# Generated by FakeRAM 2.0
VERSION 5.7 ;
BUSBITCHARS "[]" ;
PROPERTYDEFINITIONS
  MACRO width INTEGER ;
  MACRO depth INTEGER ;
  MACRO banks INTEGER ;
END PROPERTYDEFINITIONS
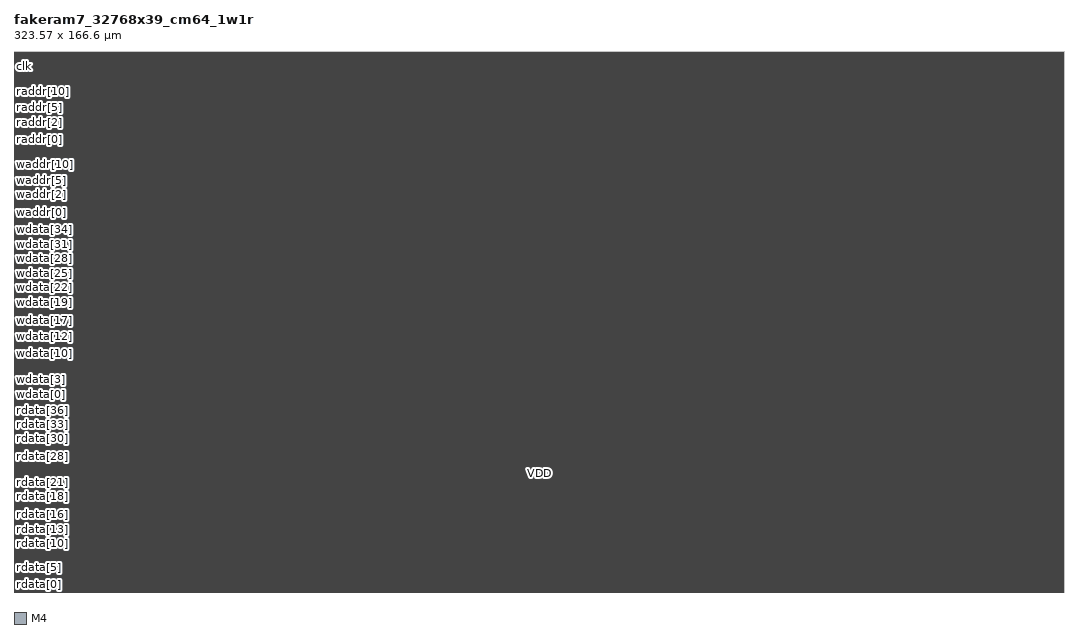
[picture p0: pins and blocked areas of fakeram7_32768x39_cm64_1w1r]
MACRO fakeram7_32768x39_cm64_1w1r
  PROPERTY width 39 ;
  PROPERTY depth 32768 ;
  PROPERTY banks 1 ;
  FOREIGN fakeram7_32768x39_cm64_1w1r 0 0 ;
  SYMMETRY X Y R90 ;
  SIZE 323.5700 BY 166.6000 ;
  CLASS BLOCK ;
  PIN wdata[0]
    DIRECTION INPUT ;
    USE SIGNAL ;
    PORT
      LAYER M4 ;
      RECT 0.00000 58.51200 0.02400 58.53600 ;
    END
  END wdata[0]
  PIN wdata[1]
    DIRECTION INPUT ;
    USE SIGNAL ;
    PORT
      LAYER M4 ;
      RECT 0.00000 60.00000 0.02400 60.02400 ;
    END
  END wdata[1]
  PIN wdata[2]
    DIRECTION INPUT ;
    USE SIGNAL ;
    PORT
      LAYER M4 ;
      RECT 0.00000 61.48800 0.02400 61.51200 ;
    END
  END wdata[2]
  PIN wdata[3]
    DIRECTION INPUT ;
    USE SIGNAL ;
    PORT
      LAYER M4 ;
      RECT 0.00000 62.97600 0.02400 63.00000 ;
    END
  END wdata[3]
  PIN wdata[4]
    DIRECTION INPUT ;
    USE SIGNAL ;
    PORT
      LAYER M4 ;
      RECT 0.00000 64.46400 0.02400 64.48800 ;
    END
  END wdata[4]
  PIN wdata[5]
    DIRECTION INPUT ;
    USE SIGNAL ;
    PORT
      LAYER M4 ;
      RECT 0.00000 65.95200 0.02400 65.97600 ;
    END
  END wdata[5]
  PIN wdata[6]
    DIRECTION INPUT ;
    USE SIGNAL ;
    PORT
      LAYER M4 ;
      RECT 0.00000 67.44000 0.02400 67.46400 ;
    END
  END wdata[6]
  PIN wdata[7]
    DIRECTION INPUT ;
    USE SIGNAL ;
    PORT
      LAYER M4 ;
      RECT 0.00000 68.92800 0.02400 68.95200 ;
    END
  END wdata[7]
  PIN wdata[8]
    DIRECTION INPUT ;
    USE SIGNAL ;
    PORT
      LAYER M4 ;
      RECT 0.00000 70.41600 0.02400 70.44000 ;
    END
  END wdata[8]
  PIN wdata[9]
    DIRECTION INPUT ;
    USE SIGNAL ;
    PORT
      LAYER M4 ;
      RECT 0.00000 71.90400 0.02400 71.92800 ;
    END
  END wdata[9]
  PIN wdata[10]
    DIRECTION INPUT ;
    USE SIGNAL ;
    PORT
      LAYER M4 ;
      RECT 0.00000 73.39200 0.02400 73.41600 ;
    END
  END wdata[10]
  PIN wdata[11]
    DIRECTION INPUT ;
    USE SIGNAL ;
    PORT
      LAYER M4 ;
      RECT 0.00000 74.88000 0.02400 74.90400 ;
    END
  END wdata[11]
  PIN wdata[12]
    DIRECTION INPUT ;
    USE SIGNAL ;
    PORT
      LAYER M4 ;
      RECT 0.00000 76.36800 0.02400 76.39200 ;
    END
  END wdata[12]
  PIN wdata[13]
    DIRECTION INPUT ;
    USE SIGNAL ;
    PORT
      LAYER M4 ;
      RECT 0.00000 77.85600 0.02400 77.88000 ;
    END
  END wdata[13]
  PIN wdata[14]
    DIRECTION INPUT ;
    USE SIGNAL ;
    PORT
      LAYER M4 ;
      RECT 0.00000 79.34400 0.02400 79.36800 ;
    END
  END wdata[14]
  PIN wdata[15]
    DIRECTION INPUT ;
    USE SIGNAL ;
    PORT
      LAYER M4 ;
      RECT 0.00000 80.83200 0.02400 80.85600 ;
    END
  END wdata[15]
  PIN wdata[16]
    DIRECTION INPUT ;
    USE SIGNAL ;
    PORT
      LAYER M4 ;
      RECT 0.00000 82.32000 0.02400 82.34400 ;
    END
  END wdata[16]
  PIN wdata[17]
    DIRECTION INPUT ;
    USE SIGNAL ;
    PORT
      LAYER M4 ;
      RECT 0.00000 83.80800 0.02400 83.83200 ;
    END
  END wdata[17]
  PIN wdata[18]
    DIRECTION INPUT ;
    USE SIGNAL ;
    PORT
      LAYER M4 ;
      RECT 0.00000 85.29600 0.02400 85.32000 ;
    END
  END wdata[18]
  PIN wdata[19]
    DIRECTION INPUT ;
    USE SIGNAL ;
    PORT
      LAYER M4 ;
      RECT 0.00000 86.78400 0.02400 86.80800 ;
    END
  END wdata[19]
  PIN wdata[20]
    DIRECTION INPUT ;
    USE SIGNAL ;
    PORT
      LAYER M4 ;
      RECT 0.00000 88.27200 0.02400 88.29600 ;
    END
  END wdata[20]
  PIN wdata[21]
    DIRECTION INPUT ;
    USE SIGNAL ;
    PORT
      LAYER M4 ;
      RECT 0.00000 89.76000 0.02400 89.78400 ;
    END
  END wdata[21]
  PIN wdata[22]
    DIRECTION INPUT ;
    USE SIGNAL ;
    PORT
      LAYER M4 ;
      RECT 0.00000 91.24800 0.02400 91.27200 ;
    END
  END wdata[22]
  PIN wdata[23]
    DIRECTION INPUT ;
    USE SIGNAL ;
    PORT
      LAYER M4 ;
      RECT 0.00000 92.73600 0.02400 92.76000 ;
    END
  END wdata[23]
  PIN wdata[24]
    DIRECTION INPUT ;
    USE SIGNAL ;
    PORT
      LAYER M4 ;
      RECT 0.00000 94.22400 0.02400 94.24800 ;
    END
  END wdata[24]
  PIN wdata[25]
    DIRECTION INPUT ;
    USE SIGNAL ;
    PORT
      LAYER M4 ;
      RECT 0.00000 95.71200 0.02400 95.73600 ;
    END
  END wdata[25]
  PIN wdata[26]
    DIRECTION INPUT ;
    USE SIGNAL ;
    PORT
      LAYER M4 ;
      RECT 0.00000 97.20000 0.02400 97.22400 ;
    END
  END wdata[26]
  PIN wdata[27]
    DIRECTION INPUT ;
    USE SIGNAL ;
    PORT
      LAYER M4 ;
      RECT 0.00000 98.68800 0.02400 98.71200 ;
    END
  END wdata[27]
  PIN wdata[28]
    DIRECTION INPUT ;
    USE SIGNAL ;
    PORT
      LAYER M4 ;
      RECT 0.00000 100.17600 0.02400 100.20000 ;
    END
  END wdata[28]
  PIN wdata[29]
    DIRECTION INPUT ;
    USE SIGNAL ;
    PORT
      LAYER M4 ;
      RECT 0.00000 101.66400 0.02400 101.68800 ;
    END
  END wdata[29]
  PIN wdata[30]
    DIRECTION INPUT ;
    USE SIGNAL ;
    PORT
      LAYER M4 ;
      RECT 0.00000 103.15200 0.02400 103.17600 ;
    END
  END wdata[30]
  PIN wdata[31]
    DIRECTION INPUT ;
    USE SIGNAL ;
    PORT
      LAYER M4 ;
      RECT 0.00000 104.64000 0.02400 104.66400 ;
    END
  END wdata[31]
  PIN wdata[32]
    DIRECTION INPUT ;
    USE SIGNAL ;
    PORT
      LAYER M4 ;
      RECT 0.00000 106.12800 0.02400 106.15200 ;
    END
  END wdata[32]
  PIN wdata[33]
    DIRECTION INPUT ;
    USE SIGNAL ;
    PORT
      LAYER M4 ;
      RECT 0.00000 107.61600 0.02400 107.64000 ;
    END
  END wdata[33]
  PIN wdata[34]
    DIRECTION INPUT ;
    USE SIGNAL ;
    PORT
      LAYER M4 ;
      RECT 0.00000 109.10400 0.02400 109.12800 ;
    END
  END wdata[34]
  PIN wdata[35]
    DIRECTION INPUT ;
    USE SIGNAL ;
    PORT
      LAYER M4 ;
      RECT 0.00000 110.59200 0.02400 110.61600 ;
    END
  END wdata[35]
  PIN wdata[36]
    DIRECTION INPUT ;
    USE SIGNAL ;
    PORT
      LAYER M4 ;
      RECT 0.00000 112.08000 0.02400 112.10400 ;
    END
  END wdata[36]
  PIN wdata[37]
    DIRECTION INPUT ;
    USE SIGNAL ;
    PORT
      LAYER M4 ;
      RECT 0.00000 113.56800 0.02400 113.59200 ;
    END
  END wdata[37]
  PIN wdata[38]
    DIRECTION INPUT ;
    USE SIGNAL ;
    PORT
      LAYER M4 ;
      RECT 0.00000 115.05600 0.02400 115.08000 ;
    END
  END wdata[38]
  PIN waddr[0]
    DIRECTION INPUT ;
    USE SIGNAL ;
    PORT
      LAYER M4 ;
      RECT 0.00000 116.97600 0.02400 117.00000 ;
    END
  END waddr[0]
  PIN waddr[1]
    DIRECTION INPUT ;
    USE SIGNAL ;
    PORT
      LAYER M4 ;
      RECT 0.00000 118.46400 0.02400 118.48800 ;
    END
  END waddr[1]
  PIN waddr[2]
    DIRECTION INPUT ;
    USE SIGNAL ;
    PORT
      LAYER M4 ;
      RECT 0.00000 119.95200 0.02400 119.97600 ;
    END
  END waddr[2]
  PIN waddr[3]
    DIRECTION INPUT ;
    USE SIGNAL ;
    PORT
      LAYER M4 ;
      RECT 0.00000 121.44000 0.02400 121.46400 ;
    END
  END waddr[3]
  PIN waddr[4]
    DIRECTION INPUT ;
    USE SIGNAL ;
    PORT
      LAYER M4 ;
      RECT 0.00000 122.92800 0.02400 122.95200 ;
    END
  END waddr[4]
  PIN waddr[5]
    DIRECTION INPUT ;
    USE SIGNAL ;
    PORT
      LAYER M4 ;
      RECT 0.00000 124.41600 0.02400 124.44000 ;
    END
  END waddr[5]
  PIN waddr[6]
    DIRECTION INPUT ;
    USE SIGNAL ;
    PORT
      LAYER M4 ;
      RECT 0.00000 125.90400 0.02400 125.92800 ;
    END
  END waddr[6]
  PIN waddr[7]
    DIRECTION INPUT ;
    USE SIGNAL ;
    PORT
      LAYER M4 ;
      RECT 0.00000 127.39200 0.02400 127.41600 ;
    END
  END waddr[7]
  PIN waddr[8]
    DIRECTION INPUT ;
    USE SIGNAL ;
    PORT
      LAYER M4 ;
      RECT 0.00000 128.88000 0.02400 128.90400 ;
    END
  END waddr[8]
  PIN waddr[9]
    DIRECTION INPUT ;
    USE SIGNAL ;
    PORT
      LAYER M4 ;
      RECT 0.00000 130.36800 0.02400 130.39200 ;
    END
  END waddr[9]
  PIN waddr[10]
    DIRECTION INPUT ;
    USE SIGNAL ;
    PORT
      LAYER M4 ;
      RECT 0.00000 131.85600 0.02400 131.88000 ;
    END
  END waddr[10]
  PIN waddr[11]
    DIRECTION INPUT ;
    USE SIGNAL ;
    PORT
      LAYER M4 ;
      RECT 0.00000 133.34400 0.02400 133.36800 ;
    END
  END waddr[11]
  PIN waddr[12]
    DIRECTION INPUT ;
    USE SIGNAL ;
    PORT
      LAYER M4 ;
      RECT 0.00000 134.83200 0.02400 134.85600 ;
    END
  END waddr[12]
  PIN waddr[13]
    DIRECTION INPUT ;
    USE SIGNAL ;
    PORT
      LAYER M4 ;
      RECT 0.00000 136.32000 0.02400 136.34400 ;
    END
  END waddr[13]
  PIN waddr[14]
    DIRECTION INPUT ;
    USE SIGNAL ;
    PORT
      LAYER M4 ;
      RECT 0.00000 137.80800 0.02400 137.83200 ;
    END
  END waddr[14]
  PIN rdata[0]
    DIRECTION OUTPUT ;
    USE SIGNAL ;
    PORT
      LAYER M4 ;
      RECT 0.00000 0.04800 0.02400 0.07200 ;
    END
  END rdata[0]
  PIN rdata[1]
    DIRECTION OUTPUT ;
    USE SIGNAL ;
    PORT
      LAYER M4 ;
      RECT 0.00000 1.53600 0.02400 1.56000 ;
    END
  END rdata[1]
  PIN rdata[2]
    DIRECTION OUTPUT ;
    USE SIGNAL ;
    PORT
      LAYER M4 ;
      RECT 0.00000 3.02400 0.02400 3.04800 ;
    END
  END rdata[2]
  PIN rdata[3]
    DIRECTION OUTPUT ;
    USE SIGNAL ;
    PORT
      LAYER M4 ;
      RECT 0.00000 4.51200 0.02400 4.53600 ;
    END
  END rdata[3]
  PIN rdata[4]
    DIRECTION OUTPUT ;
    USE SIGNAL ;
    PORT
      LAYER M4 ;
      RECT 0.00000 6.00000 0.02400 6.02400 ;
    END
  END rdata[4]
  PIN rdata[5]
    DIRECTION OUTPUT ;
    USE SIGNAL ;
    PORT
      LAYER M4 ;
      RECT 0.00000 7.48800 0.02400 7.51200 ;
    END
  END rdata[5]
  PIN rdata[6]
    DIRECTION OUTPUT ;
    USE SIGNAL ;
    PORT
      LAYER M4 ;
      RECT 0.00000 8.97600 0.02400 9.00000 ;
    END
  END rdata[6]
  PIN rdata[7]
    DIRECTION OUTPUT ;
    USE SIGNAL ;
    PORT
      LAYER M4 ;
      RECT 0.00000 10.46400 0.02400 10.48800 ;
    END
  END rdata[7]
  PIN rdata[8]
    DIRECTION OUTPUT ;
    USE SIGNAL ;
    PORT
      LAYER M4 ;
      RECT 0.00000 11.95200 0.02400 11.97600 ;
    END
  END rdata[8]
  PIN rdata[9]
    DIRECTION OUTPUT ;
    USE SIGNAL ;
    PORT
      LAYER M4 ;
      RECT 0.00000 13.44000 0.02400 13.46400 ;
    END
  END rdata[9]
  PIN rdata[10]
    DIRECTION OUTPUT ;
    USE SIGNAL ;
    PORT
      LAYER M4 ;
      RECT 0.00000 14.92800 0.02400 14.95200 ;
    END
  END rdata[10]
  PIN rdata[11]
    DIRECTION OUTPUT ;
    USE SIGNAL ;
    PORT
      LAYER M4 ;
      RECT 0.00000 16.41600 0.02400 16.44000 ;
    END
  END rdata[11]
  PIN rdata[12]
    DIRECTION OUTPUT ;
    USE SIGNAL ;
    PORT
      LAYER M4 ;
      RECT 0.00000 17.90400 0.02400 17.92800 ;
    END
  END rdata[12]
  PIN rdata[13]
    DIRECTION OUTPUT ;
    USE SIGNAL ;
    PORT
      LAYER M4 ;
      RECT 0.00000 19.39200 0.02400 19.41600 ;
    END
  END rdata[13]
  PIN rdata[14]
    DIRECTION OUTPUT ;
    USE SIGNAL ;
    PORT
      LAYER M4 ;
      RECT 0.00000 20.88000 0.02400 20.90400 ;
    END
  END rdata[14]
  PIN rdata[15]
    DIRECTION OUTPUT ;
    USE SIGNAL ;
    PORT
      LAYER M4 ;
      RECT 0.00000 22.36800 0.02400 22.39200 ;
    END
  END rdata[15]
  PIN rdata[16]
    DIRECTION OUTPUT ;
    USE SIGNAL ;
    PORT
      LAYER M4 ;
      RECT 0.00000 23.85600 0.02400 23.88000 ;
    END
  END rdata[16]
  PIN rdata[17]
    DIRECTION OUTPUT ;
    USE SIGNAL ;
    PORT
      LAYER M4 ;
      RECT 0.00000 25.34400 0.02400 25.36800 ;
    END
  END rdata[17]
  PIN rdata[18]
    DIRECTION OUTPUT ;
    USE SIGNAL ;
    PORT
      LAYER M4 ;
      RECT 0.00000 26.83200 0.02400 26.85600 ;
    END
  END rdata[18]
  PIN rdata[19]
    DIRECTION OUTPUT ;
    USE SIGNAL ;
    PORT
      LAYER M4 ;
      RECT 0.00000 28.32000 0.02400 28.34400 ;
    END
  END rdata[19]
  PIN rdata[20]
    DIRECTION OUTPUT ;
    USE SIGNAL ;
    PORT
      LAYER M4 ;
      RECT 0.00000 29.80800 0.02400 29.83200 ;
    END
  END rdata[20]
  PIN rdata[21]
    DIRECTION OUTPUT ;
    USE SIGNAL ;
    PORT
      LAYER M4 ;
      RECT 0.00000 31.29600 0.02400 31.32000 ;
    END
  END rdata[21]
  PIN rdata[22]
    DIRECTION OUTPUT ;
    USE SIGNAL ;
    PORT
      LAYER M4 ;
      RECT 0.00000 32.78400 0.02400 32.80800 ;
    END
  END rdata[22]
  PIN rdata[23]
    DIRECTION OUTPUT ;
    USE SIGNAL ;
    PORT
      LAYER M4 ;
      RECT 0.00000 34.27200 0.02400 34.29600 ;
    END
  END rdata[23]
  PIN rdata[24]
    DIRECTION OUTPUT ;
    USE SIGNAL ;
    PORT
      LAYER M4 ;
      RECT 0.00000 35.76000 0.02400 35.78400 ;
    END
  END rdata[24]
  PIN rdata[25]
    DIRECTION OUTPUT ;
    USE SIGNAL ;
    PORT
      LAYER M4 ;
      RECT 0.00000 37.24800 0.02400 37.27200 ;
    END
  END rdata[25]
  PIN rdata[26]
    DIRECTION OUTPUT ;
    USE SIGNAL ;
    PORT
      LAYER M4 ;
      RECT 0.00000 38.73600 0.02400 38.76000 ;
    END
  END rdata[26]
  PIN rdata[27]
    DIRECTION OUTPUT ;
    USE SIGNAL ;
    PORT
      LAYER M4 ;
      RECT 0.00000 40.22400 0.02400 40.24800 ;
    END
  END rdata[27]
  PIN rdata[28]
    DIRECTION OUTPUT ;
    USE SIGNAL ;
    PORT
      LAYER M4 ;
      RECT 0.00000 41.71200 0.02400 41.73600 ;
    END
  END rdata[28]
  PIN rdata[29]
    DIRECTION OUTPUT ;
    USE SIGNAL ;
    PORT
      LAYER M4 ;
      RECT 0.00000 43.20000 0.02400 43.22400 ;
    END
  END rdata[29]
  PIN rdata[30]
    DIRECTION OUTPUT ;
    USE SIGNAL ;
    PORT
      LAYER M4 ;
      RECT 0.00000 44.68800 0.02400 44.71200 ;
    END
  END rdata[30]
  PIN rdata[31]
    DIRECTION OUTPUT ;
    USE SIGNAL ;
    PORT
      LAYER M4 ;
      RECT 0.00000 46.17600 0.02400 46.20000 ;
    END
  END rdata[31]
  PIN rdata[32]
    DIRECTION OUTPUT ;
    USE SIGNAL ;
    PORT
      LAYER M4 ;
      RECT 0.00000 47.66400 0.02400 47.68800 ;
    END
  END rdata[32]
  PIN rdata[33]
    DIRECTION OUTPUT ;
    USE SIGNAL ;
    PORT
      LAYER M4 ;
      RECT 0.00000 49.15200 0.02400 49.17600 ;
    END
  END rdata[33]
  PIN rdata[34]
    DIRECTION OUTPUT ;
    USE SIGNAL ;
    PORT
      LAYER M4 ;
      RECT 0.00000 50.64000 0.02400 50.66400 ;
    END
  END rdata[34]
  PIN rdata[35]
    DIRECTION OUTPUT ;
    USE SIGNAL ;
    PORT
      LAYER M4 ;
      RECT 0.00000 52.12800 0.02400 52.15200 ;
    END
  END rdata[35]
  PIN rdata[36]
    DIRECTION OUTPUT ;
    USE SIGNAL ;
    PORT
      LAYER M4 ;
      RECT 0.00000 53.61600 0.02400 53.64000 ;
    END
  END rdata[36]
  PIN rdata[37]
    DIRECTION OUTPUT ;
    USE SIGNAL ;
    PORT
      LAYER M4 ;
      RECT 0.00000 55.10400 0.02400 55.12800 ;
    END
  END rdata[37]
  PIN rdata[38]
    DIRECTION OUTPUT ;
    USE SIGNAL ;
    PORT
      LAYER M4 ;
      RECT 0.00000 56.59200 0.02400 56.61600 ;
    END
  END rdata[38]
  PIN raddr[0]
    DIRECTION INPUT ;
    USE SIGNAL ;
    PORT
      LAYER M4 ;
      RECT 0.00000 139.29600 0.02400 139.32000 ;
    END
  END raddr[0]
  PIN raddr[1]
    DIRECTION INPUT ;
    USE SIGNAL ;
    PORT
      LAYER M4 ;
      RECT 0.00000 140.78400 0.02400 140.80800 ;
    END
  END raddr[1]
  PIN raddr[2]
    DIRECTION INPUT ;
    USE SIGNAL ;
    PORT
      LAYER M4 ;
      RECT 0.00000 142.27200 0.02400 142.29600 ;
    END
  END raddr[2]
  PIN raddr[3]
    DIRECTION INPUT ;
    USE SIGNAL ;
    PORT
      LAYER M4 ;
      RECT 0.00000 143.76000 0.02400 143.78400 ;
    END
  END raddr[3]
  PIN raddr[4]
    DIRECTION INPUT ;
    USE SIGNAL ;
    PORT
      LAYER M4 ;
      RECT 0.00000 145.24800 0.02400 145.27200 ;
    END
  END raddr[4]
  PIN raddr[5]
    DIRECTION INPUT ;
    USE SIGNAL ;
    PORT
      LAYER M4 ;
      RECT 0.00000 146.73600 0.02400 146.76000 ;
    END
  END raddr[5]
  PIN raddr[6]
    DIRECTION INPUT ;
    USE SIGNAL ;
    PORT
      LAYER M4 ;
      RECT 0.00000 148.22400 0.02400 148.24800 ;
    END
  END raddr[6]
  PIN raddr[7]
    DIRECTION INPUT ;
    USE SIGNAL ;
    PORT
      LAYER M4 ;
      RECT 0.00000 149.71200 0.02400 149.73600 ;
    END
  END raddr[7]
  PIN raddr[8]
    DIRECTION INPUT ;
    USE SIGNAL ;
    PORT
      LAYER M4 ;
      RECT 0.00000 151.20000 0.02400 151.22400 ;
    END
  END raddr[8]
  PIN raddr[9]
    DIRECTION INPUT ;
    USE SIGNAL ;
    PORT
      LAYER M4 ;
      RECT 0.00000 152.68800 0.02400 152.71200 ;
    END
  END raddr[9]
  PIN raddr[10]
    DIRECTION INPUT ;
    USE SIGNAL ;
    PORT
      LAYER M4 ;
      RECT 0.00000 154.17600 0.02400 154.20000 ;
    END
  END raddr[10]
  PIN raddr[11]
    DIRECTION INPUT ;
    USE SIGNAL ;
    PORT
      LAYER M4 ;
      RECT 0.00000 155.66400 0.02400 155.68800 ;
    END
  END raddr[11]
  PIN raddr[12]
    DIRECTION INPUT ;
    USE SIGNAL ;
    PORT
      LAYER M4 ;
      RECT 0.00000 157.15200 0.02400 157.17600 ;
    END
  END raddr[12]
  PIN raddr[13]
    DIRECTION INPUT ;
    USE SIGNAL ;
    PORT
      LAYER M4 ;
      RECT 0.00000 158.64000 0.02400 158.66400 ;
    END
  END raddr[13]
  PIN raddr[14]
    DIRECTION INPUT ;
    USE SIGNAL ;
    PORT
      LAYER M4 ;
      RECT 0.00000 160.12800 0.02400 160.15200 ;
    END
  END raddr[14]
  PIN we
    DIRECTION INPUT ;
    USE SIGNAL ;
    PORT
      LAYER M4 ;
      RECT 0.00000 163.53600 0.02400 163.56000 ;
    END
  END we
  PIN clk
    DIRECTION INPUT ;
    USE SIGNAL ;
    PORT
      LAYER M4 ;
      RECT 0.00000 162.04800 0.02400 162.07200 ;
    END
  END clk
  PIN re
    DIRECTION INPUT ;
    USE SIGNAL ;
    PORT
      LAYER M4 ;
      RECT 0.00000 165.02400 0.02400 165.04800 ;
    END
  END re
  PIN VDD
    DIRECTION INOUT ;
    USE POWER ;
    PORT
      LAYER M4 ;
      RECT 0.04800 0.38400 323.52200 0.48000 ;
      RECT 0.04800 1.15200 323.52200 1.24800 ;
      RECT 0.04800 1.92000 323.52200 2.01600 ;
      RECT 0.04800 2.68800 323.52200 2.78400 ;
      RECT 0.04800 3.45600 323.52200 3.55200 ;
      RECT 0.04800 4.22400 323.52200 4.32000 ;
      RECT 0.04800 4.99200 323.52200 5.08800 ;
      RECT 0.04800 5.76000 323.52200 5.85600 ;
      RECT 0.04800 6.52800 323.52200 6.62400 ;
      RECT 0.04800 7.29600 323.52200 7.39200 ;
      RECT 0.04800 8.06400 323.52200 8.16000 ;
      RECT 0.04800 8.83200 323.52200 8.92800 ;
      RECT 0.04800 9.60000 323.52200 9.69600 ;
      RECT 0.04800 10.36800 323.52200 10.46400 ;
      RECT 0.04800 11.13600 323.52200 11.23200 ;
      RECT 0.04800 11.90400 323.52200 12.00000 ;
      RECT 0.04800 12.67200 323.52200 12.76800 ;
      RECT 0.04800 13.44000 323.52200 13.53600 ;
      RECT 0.04800 14.20800 323.52200 14.30400 ;
      RECT 0.04800 14.97600 323.52200 15.07200 ;
      RECT 0.04800 15.74400 323.52200 15.84000 ;
      RECT 0.04800 16.51200 323.52200 16.60800 ;
      RECT 0.04800 17.28000 323.52200 17.37600 ;
      RECT 0.04800 18.04800 323.52200 18.14400 ;
      RECT 0.04800 18.81600 323.52200 18.91200 ;
      RECT 0.04800 19.58400 323.52200 19.68000 ;
      RECT 0.04800 20.35200 323.52200 20.44800 ;
      RECT 0.04800 21.12000 323.52200 21.21600 ;
      RECT 0.04800 21.88800 323.52200 21.98400 ;
      RECT 0.04800 22.65600 323.52200 22.75200 ;
      RECT 0.04800 23.42400 323.52200 23.52000 ;
      RECT 0.04800 24.19200 323.52200 24.28800 ;
      RECT 0.04800 24.96000 323.52200 25.05600 ;
      RECT 0.04800 25.72800 323.52200 25.82400 ;
      RECT 0.04800 26.49600 323.52200 26.59200 ;
      RECT 0.04800 27.26400 323.52200 27.36000 ;
      RECT 0.04800 28.03200 323.52200 28.12800 ;
      RECT 0.04800 28.80000 323.52200 28.89600 ;
      RECT 0.04800 29.56800 323.52200 29.66400 ;
      RECT 0.04800 30.33600 323.52200 30.43200 ;
      RECT 0.04800 31.10400 323.52200 31.20000 ;
      RECT 0.04800 31.87200 323.52200 31.96800 ;
      RECT 0.04800 32.64000 323.52200 32.73600 ;
      RECT 0.04800 33.40800 323.52200 33.50400 ;
      RECT 0.04800 34.17600 323.52200 34.27200 ;
      RECT 0.04800 34.94400 323.52200 35.04000 ;
      RECT 0.04800 35.71200 323.52200 35.80800 ;
      RECT 0.04800 36.48000 323.52200 36.57600 ;
      RECT 0.04800 37.24800 323.52200 37.34400 ;
      RECT 0.04800 38.01600 323.52200 38.11200 ;
      RECT 0.04800 38.78400 323.52200 38.88000 ;
      RECT 0.04800 39.55200 323.52200 39.64800 ;
      RECT 0.04800 40.32000 323.52200 40.41600 ;
      RECT 0.04800 41.08800 323.52200 41.18400 ;
      RECT 0.04800 41.85600 323.52200 41.95200 ;
      RECT 0.04800 42.62400 323.52200 42.72000 ;
      RECT 0.04800 43.39200 323.52200 43.48800 ;
      RECT 0.04800 44.16000 323.52200 44.25600 ;
      RECT 0.04800 44.92800 323.52200 45.02400 ;
      RECT 0.04800 45.69600 323.52200 45.79200 ;
      RECT 0.04800 46.46400 323.52200 46.56000 ;
      RECT 0.04800 47.23200 323.52200 47.32800 ;
      RECT 0.04800 48.00000 323.52200 48.09600 ;
      RECT 0.04800 48.76800 323.52200 48.86400 ;
      RECT 0.04800 49.53600 323.52200 49.63200 ;
      RECT 0.04800 50.30400 323.52200 50.40000 ;
      RECT 0.04800 51.07200 323.52200 51.16800 ;
      RECT 0.04800 51.84000 323.52200 51.93600 ;
      RECT 0.04800 52.60800 323.52200 52.70400 ;
      RECT 0.04800 53.37600 323.52200 53.47200 ;
      RECT 0.04800 54.14400 323.52200 54.24000 ;
      RECT 0.04800 54.91200 323.52200 55.00800 ;
      RECT 0.04800 55.68000 323.52200 55.77600 ;
      RECT 0.04800 56.44800 323.52200 56.54400 ;
      RECT 0.04800 57.21600 323.52200 57.31200 ;
      RECT 0.04800 57.98400 323.52200 58.08000 ;
      RECT 0.04800 58.75200 323.52200 58.84800 ;
      RECT 0.04800 59.52000 323.52200 59.61600 ;
      RECT 0.04800 60.28800 323.52200 60.38400 ;
      RECT 0.04800 61.05600 323.52200 61.15200 ;
      RECT 0.04800 61.82400 323.52200 61.92000 ;
      RECT 0.04800 62.59200 323.52200 62.68800 ;
      RECT 0.04800 63.36000 323.52200 63.45600 ;
      RECT 0.04800 64.12800 323.52200 64.22400 ;
      RECT 0.04800 64.89600 323.52200 64.99200 ;
      RECT 0.04800 65.66400 323.52200 65.76000 ;
      RECT 0.04800 66.43200 323.52200 66.52800 ;
      RECT 0.04800 67.20000 323.52200 67.29600 ;
      RECT 0.04800 67.96800 323.52200 68.06400 ;
      RECT 0.04800 68.73600 323.52200 68.83200 ;
      RECT 0.04800 69.50400 323.52200 69.60000 ;
      RECT 0.04800 70.27200 323.52200 70.36800 ;
      RECT 0.04800 71.04000 323.52200 71.13600 ;
      RECT 0.04800 71.80800 323.52200 71.90400 ;
      RECT 0.04800 72.57600 323.52200 72.67200 ;
      RECT 0.04800 73.34400 323.52200 73.44000 ;
      RECT 0.04800 74.11200 323.52200 74.20800 ;
      RECT 0.04800 74.88000 323.52200 74.97600 ;
      RECT 0.04800 75.64800 323.52200 75.74400 ;
      RECT 0.04800 76.41600 323.52200 76.51200 ;
      RECT 0.04800 77.18400 323.52200 77.28000 ;
      RECT 0.04800 77.95200 323.52200 78.04800 ;
      RECT 0.04800 78.72000 323.52200 78.81600 ;
      RECT 0.04800 79.48800 323.52200 79.58400 ;
      RECT 0.04800 80.25600 323.52200 80.35200 ;
      RECT 0.04800 81.02400 323.52200 81.12000 ;
      RECT 0.04800 81.79200 323.52200 81.88800 ;
      RECT 0.04800 82.56000 323.52200 82.65600 ;
      RECT 0.04800 83.32800 323.52200 83.42400 ;
      RECT 0.04800 84.09600 323.52200 84.19200 ;
      RECT 0.04800 84.86400 323.52200 84.96000 ;
      RECT 0.04800 85.63200 323.52200 85.72800 ;
      RECT 0.04800 86.40000 323.52200 86.49600 ;
      RECT 0.04800 87.16800 323.52200 87.26400 ;
      RECT 0.04800 87.93600 323.52200 88.03200 ;
      RECT 0.04800 88.70400 323.52200 88.80000 ;
      RECT 0.04800 89.47200 323.52200 89.56800 ;
      RECT 0.04800 90.24000 323.52200 90.33600 ;
      RECT 0.04800 91.00800 323.52200 91.10400 ;
      RECT 0.04800 91.77600 323.52200 91.87200 ;
      RECT 0.04800 92.54400 323.52200 92.64000 ;
      RECT 0.04800 93.31200 323.52200 93.40800 ;
      RECT 0.04800 94.08000 323.52200 94.17600 ;
      RECT 0.04800 94.84800 323.52200 94.94400 ;
      RECT 0.04800 95.61600 323.52200 95.71200 ;
      RECT 0.04800 96.38400 323.52200 96.48000 ;
      RECT 0.04800 97.15200 323.52200 97.24800 ;
      RECT 0.04800 97.92000 323.52200 98.01600 ;
      RECT 0.04800 98.68800 323.52200 98.78400 ;
      RECT 0.04800 99.45600 323.52200 99.55200 ;
      RECT 0.04800 100.22400 323.52200 100.32000 ;
      RECT 0.04800 100.99200 323.52200 101.08800 ;
      RECT 0.04800 101.76000 323.52200 101.85600 ;
      RECT 0.04800 102.52800 323.52200 102.62400 ;
      RECT 0.04800 103.29600 323.52200 103.39200 ;
      RECT 0.04800 104.06400 323.52200 104.16000 ;
      RECT 0.04800 104.83200 323.52200 104.92800 ;
      RECT 0.04800 105.60000 323.52200 105.69600 ;
      RECT 0.04800 106.36800 323.52200 106.46400 ;
      RECT 0.04800 107.13600 323.52200 107.23200 ;
      RECT 0.04800 107.90400 323.52200 108.00000 ;
      RECT 0.04800 108.67200 323.52200 108.76800 ;
      RECT 0.04800 109.44000 323.52200 109.53600 ;
      RECT 0.04800 110.20800 323.52200 110.30400 ;
      RECT 0.04800 110.97600 323.52200 111.07200 ;
      RECT 0.04800 111.74400 323.52200 111.84000 ;
      RECT 0.04800 112.51200 323.52200 112.60800 ;
      RECT 0.04800 113.28000 323.52200 113.37600 ;
      RECT 0.04800 114.04800 323.52200 114.14400 ;
      RECT 0.04800 114.81600 323.52200 114.91200 ;
      RECT 0.04800 115.58400 323.52200 115.68000 ;
      RECT 0.04800 116.35200 323.52200 116.44800 ;
      RECT 0.04800 117.12000 323.52200 117.21600 ;
      RECT 0.04800 117.88800 323.52200 117.98400 ;
      RECT 0.04800 118.65600 323.52200 118.75200 ;
      RECT 0.04800 119.42400 323.52200 119.52000 ;
      RECT 0.04800 120.19200 323.52200 120.28800 ;
      RECT 0.04800 120.96000 323.52200 121.05600 ;
      RECT 0.04800 121.72800 323.52200 121.82400 ;
      RECT 0.04800 122.49600 323.52200 122.59200 ;
      RECT 0.04800 123.26400 323.52200 123.36000 ;
      RECT 0.04800 124.03200 323.52200 124.12800 ;
      RECT 0.04800 124.80000 323.52200 124.89600 ;
      RECT 0.04800 125.56800 323.52200 125.66400 ;
      RECT 0.04800 126.33600 323.52200 126.43200 ;
      RECT 0.04800 127.10400 323.52200 127.20000 ;
      RECT 0.04800 127.87200 323.52200 127.96800 ;
      RECT 0.04800 128.64000 323.52200 128.73600 ;
      RECT 0.04800 129.40800 323.52200 129.50400 ;
      RECT 0.04800 130.17600 323.52200 130.27200 ;
      RECT 0.04800 130.94400 323.52200 131.04000 ;
      RECT 0.04800 131.71200 323.52200 131.80800 ;
      RECT 0.04800 132.48000 323.52200 132.57600 ;
      RECT 0.04800 133.24800 323.52200 133.34400 ;
      RECT 0.04800 134.01600 323.52200 134.11200 ;
      RECT 0.04800 134.78400 323.52200 134.88000 ;
      RECT 0.04800 135.55200 323.52200 135.64800 ;
      RECT 0.04800 136.32000 323.52200 136.41600 ;
      RECT 0.04800 137.08800 323.52200 137.18400 ;
      RECT 0.04800 137.85600 323.52200 137.95200 ;
      RECT 0.04800 138.62400 323.52200 138.72000 ;
      RECT 0.04800 139.39200 323.52200 139.48800 ;
      RECT 0.04800 140.16000 323.52200 140.25600 ;
      RECT 0.04800 140.92800 323.52200 141.02400 ;
      RECT 0.04800 141.69600 323.52200 141.79200 ;
      RECT 0.04800 142.46400 323.52200 142.56000 ;
      RECT 0.04800 143.23200 323.52200 143.32800 ;
      RECT 0.04800 144.00000 323.52200 144.09600 ;
      RECT 0.04800 144.76800 323.52200 144.86400 ;
      RECT 0.04800 145.53600 323.52200 145.63200 ;
      RECT 0.04800 146.30400 323.52200 146.40000 ;
      RECT 0.04800 147.07200 323.52200 147.16800 ;
      RECT 0.04800 147.84000 323.52200 147.93600 ;
      RECT 0.04800 148.60800 323.52200 148.70400 ;
      RECT 0.04800 149.37600 323.52200 149.47200 ;
      RECT 0.04800 150.14400 323.52200 150.24000 ;
      RECT 0.04800 150.91200 323.52200 151.00800 ;
      RECT 0.04800 151.68000 323.52200 151.77600 ;
      RECT 0.04800 152.44800 323.52200 152.54400 ;
      RECT 0.04800 153.21600 323.52200 153.31200 ;
      RECT 0.04800 153.98400 323.52200 154.08000 ;
      RECT 0.04800 154.75200 323.52200 154.84800 ;
      RECT 0.04800 155.52000 323.52200 155.61600 ;
      RECT 0.04800 156.28800 323.52200 156.38400 ;
      RECT 0.04800 157.05600 323.52200 157.15200 ;
      RECT 0.04800 157.82400 323.52200 157.92000 ;
      RECT 0.04800 158.59200 323.52200 158.68800 ;
      RECT 0.04800 159.36000 323.52200 159.45600 ;
      RECT 0.04800 160.12800 323.52200 160.22400 ;
      RECT 0.04800 160.89600 323.52200 160.99200 ;
      RECT 0.04800 161.66400 323.52200 161.76000 ;
      RECT 0.04800 162.43200 323.52200 162.52800 ;
      RECT 0.04800 163.20000 323.52200 163.29600 ;
      RECT 0.04800 163.96800 323.52200 164.06400 ;
      RECT 0.04800 164.73600 323.52200 164.83200 ;
      RECT 0.04800 165.50400 323.52200 165.60000 ;
      RECT 0.04800 166.27200 323.52200 166.36800 ;
    END
  END VDD
  PIN VSS
    DIRECTION INOUT ;
    USE GROUND ;
    PORT
      LAYER M4 ;
      RECT 0.04800 0.00000 323.52200 0.09600 ;
      RECT 0.04800 0.76800 323.52200 0.86400 ;
      RECT 0.04800 1.53600 323.52200 1.63200 ;
      RECT 0.04800 2.30400 323.52200 2.40000 ;
      RECT 0.04800 3.07200 323.52200 3.16800 ;
      RECT 0.04800 3.84000 323.52200 3.93600 ;
      RECT 0.04800 4.60800 323.52200 4.70400 ;
      RECT 0.04800 5.37600 323.52200 5.47200 ;
      RECT 0.04800 6.14400 323.52200 6.24000 ;
      RECT 0.04800 6.91200 323.52200 7.00800 ;
      RECT 0.04800 7.68000 323.52200 7.77600 ;
      RECT 0.04800 8.44800 323.52200 8.54400 ;
      RECT 0.04800 9.21600 323.52200 9.31200 ;
      RECT 0.04800 9.98400 323.52200 10.08000 ;
      RECT 0.04800 10.75200 323.52200 10.84800 ;
      RECT 0.04800 11.52000 323.52200 11.61600 ;
      RECT 0.04800 12.28800 323.52200 12.38400 ;
      RECT 0.04800 13.05600 323.52200 13.15200 ;
      RECT 0.04800 13.82400 323.52200 13.92000 ;
      RECT 0.04800 14.59200 323.52200 14.68800 ;
      RECT 0.04800 15.36000 323.52200 15.45600 ;
      RECT 0.04800 16.12800 323.52200 16.22400 ;
      RECT 0.04800 16.89600 323.52200 16.99200 ;
      RECT 0.04800 17.66400 323.52200 17.76000 ;
      RECT 0.04800 18.43200 323.52200 18.52800 ;
      RECT 0.04800 19.20000 323.52200 19.29600 ;
      RECT 0.04800 19.96800 323.52200 20.06400 ;
      RECT 0.04800 20.73600 323.52200 20.83200 ;
      RECT 0.04800 21.50400 323.52200 21.60000 ;
      RECT 0.04800 22.27200 323.52200 22.36800 ;
      RECT 0.04800 23.04000 323.52200 23.13600 ;
      RECT 0.04800 23.80800 323.52200 23.90400 ;
      RECT 0.04800 24.57600 323.52200 24.67200 ;
      RECT 0.04800 25.34400 323.52200 25.44000 ;
      RECT 0.04800 26.11200 323.52200 26.20800 ;
      RECT 0.04800 26.88000 323.52200 26.97600 ;
      RECT 0.04800 27.64800 323.52200 27.74400 ;
      RECT 0.04800 28.41600 323.52200 28.51200 ;
      RECT 0.04800 29.18400 323.52200 29.28000 ;
      RECT 0.04800 29.95200 323.52200 30.04800 ;
      RECT 0.04800 30.72000 323.52200 30.81600 ;
      RECT 0.04800 31.48800 323.52200 31.58400 ;
      RECT 0.04800 32.25600 323.52200 32.35200 ;
      RECT 0.04800 33.02400 323.52200 33.12000 ;
      RECT 0.04800 33.79200 323.52200 33.88800 ;
      RECT 0.04800 34.56000 323.52200 34.65600 ;
      RECT 0.04800 35.32800 323.52200 35.42400 ;
      RECT 0.04800 36.09600 323.52200 36.19200 ;
      RECT 0.04800 36.86400 323.52200 36.96000 ;
      RECT 0.04800 37.63200 323.52200 37.72800 ;
      RECT 0.04800 38.40000 323.52200 38.49600 ;
      RECT 0.04800 39.16800 323.52200 39.26400 ;
      RECT 0.04800 39.93600 323.52200 40.03200 ;
      RECT 0.04800 40.70400 323.52200 40.80000 ;
      RECT 0.04800 41.47200 323.52200 41.56800 ;
      RECT 0.04800 42.24000 323.52200 42.33600 ;
      RECT 0.04800 43.00800 323.52200 43.10400 ;
      RECT 0.04800 43.77600 323.52200 43.87200 ;
      RECT 0.04800 44.54400 323.52200 44.64000 ;
      RECT 0.04800 45.31200 323.52200 45.40800 ;
      RECT 0.04800 46.08000 323.52200 46.17600 ;
      RECT 0.04800 46.84800 323.52200 46.94400 ;
      RECT 0.04800 47.61600 323.52200 47.71200 ;
      RECT 0.04800 48.38400 323.52200 48.48000 ;
      RECT 0.04800 49.15200 323.52200 49.24800 ;
      RECT 0.04800 49.92000 323.52200 50.01600 ;
      RECT 0.04800 50.68800 323.52200 50.78400 ;
      RECT 0.04800 51.45600 323.52200 51.55200 ;
      RECT 0.04800 52.22400 323.52200 52.32000 ;
      RECT 0.04800 52.99200 323.52200 53.08800 ;
      RECT 0.04800 53.76000 323.52200 53.85600 ;
      RECT 0.04800 54.52800 323.52200 54.62400 ;
      RECT 0.04800 55.29600 323.52200 55.39200 ;
      RECT 0.04800 56.06400 323.52200 56.16000 ;
      RECT 0.04800 56.83200 323.52200 56.92800 ;
      RECT 0.04800 57.60000 323.52200 57.69600 ;
      RECT 0.04800 58.36800 323.52200 58.46400 ;
      RECT 0.04800 59.13600 323.52200 59.23200 ;
      RECT 0.04800 59.90400 323.52200 60.00000 ;
      RECT 0.04800 60.67200 323.52200 60.76800 ;
      RECT 0.04800 61.44000 323.52200 61.53600 ;
      RECT 0.04800 62.20800 323.52200 62.30400 ;
      RECT 0.04800 62.97600 323.52200 63.07200 ;
      RECT 0.04800 63.74400 323.52200 63.84000 ;
      RECT 0.04800 64.51200 323.52200 64.60800 ;
      RECT 0.04800 65.28000 323.52200 65.37600 ;
      RECT 0.04800 66.04800 323.52200 66.14400 ;
      RECT 0.04800 66.81600 323.52200 66.91200 ;
      RECT 0.04800 67.58400 323.52200 67.68000 ;
      RECT 0.04800 68.35200 323.52200 68.44800 ;
      RECT 0.04800 69.12000 323.52200 69.21600 ;
      RECT 0.04800 69.88800 323.52200 69.98400 ;
      RECT 0.04800 70.65600 323.52200 70.75200 ;
      RECT 0.04800 71.42400 323.52200 71.52000 ;
      RECT 0.04800 72.19200 323.52200 72.28800 ;
      RECT 0.04800 72.96000 323.52200 73.05600 ;
      RECT 0.04800 73.72800 323.52200 73.82400 ;
      RECT 0.04800 74.49600 323.52200 74.59200 ;
      RECT 0.04800 75.26400 323.52200 75.36000 ;
      RECT 0.04800 76.03200 323.52200 76.12800 ;
      RECT 0.04800 76.80000 323.52200 76.89600 ;
      RECT 0.04800 77.56800 323.52200 77.66400 ;
      RECT 0.04800 78.33600 323.52200 78.43200 ;
      RECT 0.04800 79.10400 323.52200 79.20000 ;
      RECT 0.04800 79.87200 323.52200 79.96800 ;
      RECT 0.04800 80.64000 323.52200 80.73600 ;
      RECT 0.04800 81.40800 323.52200 81.50400 ;
      RECT 0.04800 82.17600 323.52200 82.27200 ;
      RECT 0.04800 82.94400 323.52200 83.04000 ;
      RECT 0.04800 83.71200 323.52200 83.80800 ;
      RECT 0.04800 84.48000 323.52200 84.57600 ;
      RECT 0.04800 85.24800 323.52200 85.34400 ;
      RECT 0.04800 86.01600 323.52200 86.11200 ;
      RECT 0.04800 86.78400 323.52200 86.88000 ;
      RECT 0.04800 87.55200 323.52200 87.64800 ;
      RECT 0.04800 88.32000 323.52200 88.41600 ;
      RECT 0.04800 89.08800 323.52200 89.18400 ;
      RECT 0.04800 89.85600 323.52200 89.95200 ;
      RECT 0.04800 90.62400 323.52200 90.72000 ;
      RECT 0.04800 91.39200 323.52200 91.48800 ;
      RECT 0.04800 92.16000 323.52200 92.25600 ;
      RECT 0.04800 92.92800 323.52200 93.02400 ;
      RECT 0.04800 93.69600 323.52200 93.79200 ;
      RECT 0.04800 94.46400 323.52200 94.56000 ;
      RECT 0.04800 95.23200 323.52200 95.32800 ;
      RECT 0.04800 96.00000 323.52200 96.09600 ;
      RECT 0.04800 96.76800 323.52200 96.86400 ;
      RECT 0.04800 97.53600 323.52200 97.63200 ;
      RECT 0.04800 98.30400 323.52200 98.40000 ;
      RECT 0.04800 99.07200 323.52200 99.16800 ;
      RECT 0.04800 99.84000 323.52200 99.93600 ;
      RECT 0.04800 100.60800 323.52200 100.70400 ;
      RECT 0.04800 101.37600 323.52200 101.47200 ;
      RECT 0.04800 102.14400 323.52200 102.24000 ;
      RECT 0.04800 102.91200 323.52200 103.00800 ;
      RECT 0.04800 103.68000 323.52200 103.77600 ;
      RECT 0.04800 104.44800 323.52200 104.54400 ;
      RECT 0.04800 105.21600 323.52200 105.31200 ;
      RECT 0.04800 105.98400 323.52200 106.08000 ;
      RECT 0.04800 106.75200 323.52200 106.84800 ;
      RECT 0.04800 107.52000 323.52200 107.61600 ;
      RECT 0.04800 108.28800 323.52200 108.38400 ;
      RECT 0.04800 109.05600 323.52200 109.15200 ;
      RECT 0.04800 109.82400 323.52200 109.92000 ;
      RECT 0.04800 110.59200 323.52200 110.68800 ;
      RECT 0.04800 111.36000 323.52200 111.45600 ;
      RECT 0.04800 112.12800 323.52200 112.22400 ;
      RECT 0.04800 112.89600 323.52200 112.99200 ;
      RECT 0.04800 113.66400 323.52200 113.76000 ;
      RECT 0.04800 114.43200 323.52200 114.52800 ;
      RECT 0.04800 115.20000 323.52200 115.29600 ;
      RECT 0.04800 115.96800 323.52200 116.06400 ;
      RECT 0.04800 116.73600 323.52200 116.83200 ;
      RECT 0.04800 117.50400 323.52200 117.60000 ;
      RECT 0.04800 118.27200 323.52200 118.36800 ;
      RECT 0.04800 119.04000 323.52200 119.13600 ;
      RECT 0.04800 119.80800 323.52200 119.90400 ;
      RECT 0.04800 120.57600 323.52200 120.67200 ;
      RECT 0.04800 121.34400 323.52200 121.44000 ;
      RECT 0.04800 122.11200 323.52200 122.20800 ;
      RECT 0.04800 122.88000 323.52200 122.97600 ;
      RECT 0.04800 123.64800 323.52200 123.74400 ;
      RECT 0.04800 124.41600 323.52200 124.51200 ;
      RECT 0.04800 125.18400 323.52200 125.28000 ;
      RECT 0.04800 125.95200 323.52200 126.04800 ;
      RECT 0.04800 126.72000 323.52200 126.81600 ;
      RECT 0.04800 127.48800 323.52200 127.58400 ;
      RECT 0.04800 128.25600 323.52200 128.35200 ;
      RECT 0.04800 129.02400 323.52200 129.12000 ;
      RECT 0.04800 129.79200 323.52200 129.88800 ;
      RECT 0.04800 130.56000 323.52200 130.65600 ;
      RECT 0.04800 131.32800 323.52200 131.42400 ;
      RECT 0.04800 132.09600 323.52200 132.19200 ;
      RECT 0.04800 132.86400 323.52200 132.96000 ;
      RECT 0.04800 133.63200 323.52200 133.72800 ;
      RECT 0.04800 134.40000 323.52200 134.49600 ;
      RECT 0.04800 135.16800 323.52200 135.26400 ;
      RECT 0.04800 135.93600 323.52200 136.03200 ;
      RECT 0.04800 136.70400 323.52200 136.80000 ;
      RECT 0.04800 137.47200 323.52200 137.56800 ;
      RECT 0.04800 138.24000 323.52200 138.33600 ;
      RECT 0.04800 139.00800 323.52200 139.10400 ;
      RECT 0.04800 139.77600 323.52200 139.87200 ;
      RECT 0.04800 140.54400 323.52200 140.64000 ;
      RECT 0.04800 141.31200 323.52200 141.40800 ;
      RECT 0.04800 142.08000 323.52200 142.17600 ;
      RECT 0.04800 142.84800 323.52200 142.94400 ;
      RECT 0.04800 143.61600 323.52200 143.71200 ;
      RECT 0.04800 144.38400 323.52200 144.48000 ;
      RECT 0.04800 145.15200 323.52200 145.24800 ;
      RECT 0.04800 145.92000 323.52200 146.01600 ;
      RECT 0.04800 146.68800 323.52200 146.78400 ;
      RECT 0.04800 147.45600 323.52200 147.55200 ;
      RECT 0.04800 148.22400 323.52200 148.32000 ;
      RECT 0.04800 148.99200 323.52200 149.08800 ;
      RECT 0.04800 149.76000 323.52200 149.85600 ;
      RECT 0.04800 150.52800 323.52200 150.62400 ;
      RECT 0.04800 151.29600 323.52200 151.39200 ;
      RECT 0.04800 152.06400 323.52200 152.16000 ;
      RECT 0.04800 152.83200 323.52200 152.92800 ;
      RECT 0.04800 153.60000 323.52200 153.69600 ;
      RECT 0.04800 154.36800 323.52200 154.46400 ;
      RECT 0.04800 155.13600 323.52200 155.23200 ;
      RECT 0.04800 155.90400 323.52200 156.00000 ;
      RECT 0.04800 156.67200 323.52200 156.76800 ;
      RECT 0.04800 157.44000 323.52200 157.53600 ;
      RECT 0.04800 158.20800 323.52200 158.30400 ;
      RECT 0.04800 158.97600 323.52200 159.07200 ;
      RECT 0.04800 159.74400 323.52200 159.84000 ;
      RECT 0.04800 160.51200 323.52200 160.60800 ;
      RECT 0.04800 161.28000 323.52200 161.37600 ;
      RECT 0.04800 162.04800 323.52200 162.14400 ;
      RECT 0.04800 162.81600 323.52200 162.91200 ;
      RECT 0.04800 163.58400 323.52200 163.68000 ;
      RECT 0.04800 164.35200 323.52200 164.44800 ;
      RECT 0.04800 165.12000 323.52200 165.21600 ;
      RECT 0.04800 165.88800 323.52200 165.98400 ;
    END
  END VSS
  OBS
    LAYER M1 ;
    RECT 0 0 323.57000 166.60000 ;
    LAYER M2 ;
    RECT 0 0 323.57000 166.60000 ;
    LAYER M3 ;
    RECT 0 0 323.57000 166.60000 ;
    LAYER M4 ;
    RECT 0 0 323.57000 166.60000 ;
  END
END fakeram7_32768x39_cm64_1w1r

END LIBRARY
